VERSION 5.7 ;
  NOWIREEXTENSIONATPIN ON ;
  DIVIDERCHAR "/" ;
  BUSBITCHARS "[]" ;
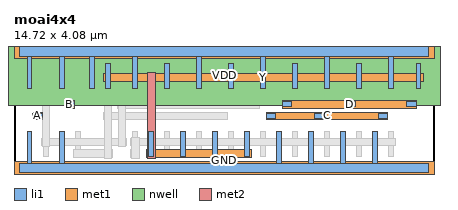
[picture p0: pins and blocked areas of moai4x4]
MACRO moai4x4
  CLASS BLOCK ;
  FOREIGN moai4x4 ;
  ORIGIN 0.000 0.000 ;
  SIZE 14.720 BY 4.080 ;
  PIN A
    ANTENNAGATEAREA 0.596400 ;
    PORT
      LAYER li1 ;
        RECT 0.665 1.745 0.995 1.915 ;
      LAYER met1 ;
        RECT 0.670 1.700 0.990 1.960 ;
    END
  END A
  PIN VDD
    ANTENNADIFFAREA 6.419800 ;
    PORT
      LAYER nwell ;
        RECT -0.230 2.200 14.950 4.410 ;
      LAYER li1 ;
        RECT 0.210 3.915 14.510 4.245 ;
        RECT 0.460 2.800 0.630 3.915 ;
        RECT 1.590 2.800 1.760 3.915 ;
        RECT 2.650 2.800 2.820 3.915 ;
        RECT 4.170 2.800 4.340 3.915 ;
        RECT 6.410 2.800 6.580 3.915 ;
        RECT 8.650 2.800 8.820 3.915 ;
        RECT 10.890 2.800 11.060 3.915 ;
        RECT 13.130 2.800 13.300 3.915 ;
      LAYER met1 ;
        RECT 0.000 3.840 14.720 4.320 ;
    END
  END VDD
  PIN GND
    ANTENNADIFFAREA 5.584000 ;
    PORT
      LAYER li1 ;
        RECT 0.460 0.165 0.630 1.280 ;
        RECT 1.590 0.165 1.760 1.280 ;
        RECT 9.210 0.165 9.380 1.280 ;
        RECT 10.330 0.165 10.500 1.280 ;
        RECT 11.450 0.165 11.620 1.280 ;
        RECT 12.570 0.165 12.740 1.280 ;
        RECT 0.210 -0.165 14.510 0.165 ;
      LAYER met1 ;
        RECT 0.000 -0.240 14.720 0.240 ;
    END
  END GND
  PIN B
    ANTENNAGATEAREA 0.596400 ;
    PORT
      LAYER li1 ;
        RECT 1.795 2.145 2.125 2.315 ;
      LAYER met1 ;
        RECT 1.800 2.100 2.120 2.360 ;
    END
  END B
  PIN D
    ANTENNAGATEAREA 1.780800 ;
    PORT
      LAYER li1 ;
        RECT 9.410 2.145 9.740 2.315 ;
        RECT 11.650 2.145 11.980 2.315 ;
        RECT 13.770 2.145 14.100 2.315 ;
      LAYER met1 ;
        RECT 9.415 2.100 14.095 2.360 ;
    END
  END D
  PIN C
    ANTENNAGATEAREA 1.780800 ;
    PORT
      LAYER li1 ;
        RECT 8.850 1.745 9.180 1.915 ;
        RECT 10.530 1.745 10.860 1.915 ;
        RECT 12.770 1.745 13.100 1.915 ;
      LAYER met1 ;
        RECT 8.855 1.700 13.095 1.960 ;
    END
  END C
  PIN Y
    ANTENNADIFFAREA 2.629200 ;
    PORT
      LAYER li1 ;
        RECT 3.210 2.800 3.380 3.680 ;
        RECT 5.290 2.800 5.460 3.680 ;
        RECT 7.530 2.800 7.700 3.680 ;
        RECT 9.770 2.800 9.940 3.680 ;
        RECT 12.010 2.800 12.180 3.680 ;
        RECT 14.090 2.800 14.260 3.680 ;
        RECT 4.730 0.400 4.900 1.280 ;
        RECT 5.850 0.400 6.020 1.280 ;
        RECT 6.970 0.400 7.140 1.280 ;
        RECT 8.090 0.400 8.260 1.280 ;
      LAYER met1 ;
        RECT 3.135 3.040 14.335 3.300 ;
        RECT 4.655 0.380 8.335 0.640 ;
      LAYER met2 ;
        RECT 4.685 0.350 4.945 3.330 ;
    END
  END Y
  OBS
      LAYER li1 ;
        RECT 1.030 2.800 1.200 3.680 ;
        RECT 2.160 2.800 2.330 3.680 ;
        RECT 3.690 2.800 3.860 3.680 ;
        RECT 4.730 2.800 4.900 3.680 ;
        RECT 5.850 2.800 6.020 3.680 ;
        RECT 6.970 2.800 7.140 3.680 ;
        RECT 8.090 2.800 8.260 3.680 ;
        RECT 9.210 2.800 9.380 3.680 ;
        RECT 10.330 2.800 10.500 3.680 ;
        RECT 11.450 2.800 11.620 3.680 ;
        RECT 12.570 2.800 12.740 3.680 ;
        RECT 13.610 2.800 13.780 3.680 ;
        RECT 4.370 2.145 4.700 2.315 ;
        RECT 6.050 2.145 6.380 2.315 ;
        RECT 8.290 2.145 8.620 2.315 ;
        RECT 3.370 1.745 3.700 1.915 ;
        RECT 4.930 1.745 5.260 1.915 ;
        RECT 7.170 1.745 7.500 1.915 ;
        RECT 1.030 0.400 1.200 1.280 ;
        RECT 2.160 0.400 2.330 1.280 ;
        RECT 4.170 0.400 4.340 1.280 ;
        RECT 5.290 0.400 5.460 1.280 ;
        RECT 6.410 0.400 6.580 1.280 ;
        RECT 7.530 0.400 7.700 1.280 ;
        RECT 8.650 0.400 8.820 1.280 ;
        RECT 9.770 0.400 9.940 1.280 ;
        RECT 10.890 0.400 11.060 1.280 ;
        RECT 12.010 0.400 12.180 1.280 ;
        RECT 13.130 0.400 13.300 1.280 ;
      LAYER met1 ;
        RECT 2.085 3.440 3.455 3.700 ;
        RECT 3.615 3.440 8.335 3.700 ;
        RECT 9.135 3.440 13.855 3.700 ;
        RECT 0.955 3.040 1.275 3.300 ;
        RECT 3.615 2.100 8.615 2.360 ;
        RECT 3.135 1.700 7.495 1.960 ;
        RECT 0.955 0.780 3.935 1.040 ;
        RECT 4.095 0.780 13.375 1.040 ;
        RECT 2.085 0.380 3.455 0.640 ;
        RECT 4.095 0.380 4.415 0.640 ;
      LAYER met2 ;
        RECT 0.985 0.750 1.245 3.330 ;
        RECT 3.165 0.350 3.425 3.730 ;
        RECT 3.645 0.750 3.905 2.390 ;
        RECT 4.125 0.350 4.385 1.070 ;
  END
END moai4x4
END LIBRARY

